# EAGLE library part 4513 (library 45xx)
BCD to 7-segment LATCH/DECODER/DRIVER

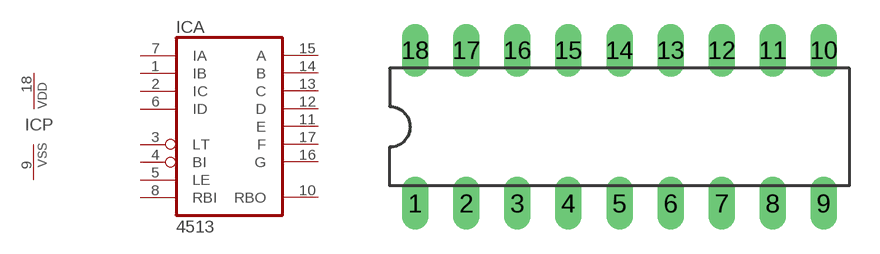
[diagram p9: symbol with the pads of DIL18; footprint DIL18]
Designator prefix IC; gates A=4513 P=PWRN

## 4513N  [DIL18]
1  A:IB  in
2  A:IC  in
3  A:LT  in
4  A:BI  in
5  A:LE  in
6  A:ID  in
7  A:IA  in
8  A:RBI  in
9  P:VSS  pwr
10  A:RBO  out
11  A:E  out
12  A:D  out
13  A:C  out
14  A:B  out
15  A:A  out
16  A:G  out
17  A:F  out
18  P:VDD  pwr

## Footprint DIL18 (pad centres in mm)
Dual In Line Package
drill 0.813 long: 1 -10.16,-3.81; 2 -7.62,-3.81; 3 -5.08,-3.81; 4 -2.54,-3.81; 5 0,-3.81; 6 2.54,-3.81; 7 5.08,-3.81; 8 7.62,-3.81; 9 10.16,-3.81; 10 10.16,3.81; 11 7.62,3.81; 12 5.08,3.81; 13 2.54,3.81; 14 0,3.81; 15 -2.54,3.81; 16 -5.08,3.81; 17 -7.62,3.81; 18 -10.16,3.81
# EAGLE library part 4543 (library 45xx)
BCD to 7-segment LCD DECODER

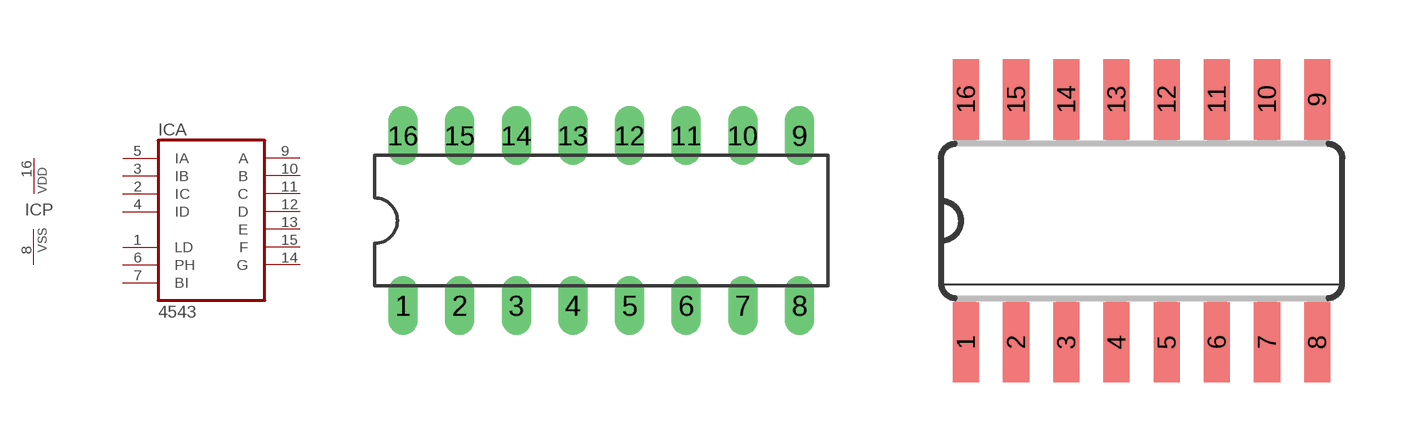
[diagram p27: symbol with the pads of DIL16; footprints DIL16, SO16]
Designator prefix IC; gates A=4543 P=PWRN

## 4543N  [DIL16]
1  A:LD  in
2  A:IC  in
3  A:IB  in
4  A:ID  in
5  A:IA  in
6  A:PH  in
7  A:BI  in
8  P:VSS  pwr
9  A:A  out
10  A:B  out
11  A:C  out
12  A:D  out
13  A:E  out
14  A:G  out
15  A:F  out
16  P:VDD  pwr

## 4543D  [SO16]
Pads as for DIL16

## Footprint DIL16 (pad centres in mm)
Dual In Line Package
drill 0.813 long: 1 -8.89,-3.81; 2 -6.35,-3.81; 3 -3.81,-3.81; 4 -1.27,-3.81; 5 1.27,-3.81; 6 3.81,-3.81; 7 6.35,-3.81; 8 8.89,-3.81; 9 8.89,3.81; 10 6.35,3.81; 11 3.81,3.81; 12 1.27,3.81; 13 -1.27,3.81; 14 -3.81,3.81; 15 -6.35,3.81; 16 -8.89,3.81

## Footprint SO16 (pad centres in mm)
Small Outline package 150 mil
smd 0.66 x 2.032: 1 -4.445,-3.073; 2 -3.175,-3.073; 3 -1.905,-3.073; 4 -0.635,-3.073; 5 0.635,-3.073; 6 1.905,-3.073; 7 3.175,-3.073; 8 4.445,-3.073; 9 4.445,3.073; 10 3.175,3.073; 11 1.905,3.073; 12 0.635,3.073; 13 -0.635,3.073; 14 -1.905,3.073; 15 -3.175,3.073; 16 -4.445,3.073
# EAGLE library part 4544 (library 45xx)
7-segment DECODER

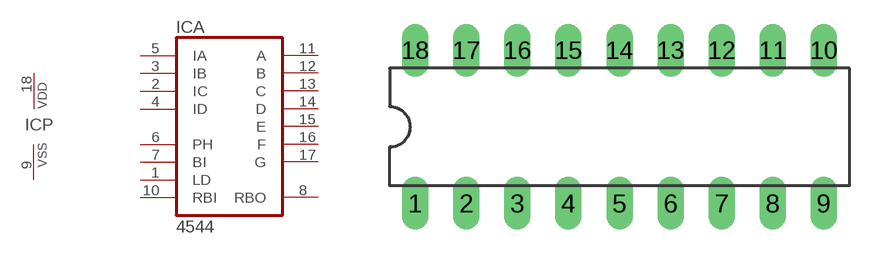
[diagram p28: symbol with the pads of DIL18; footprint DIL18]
Designator prefix IC; gates A=4544 P=PWRN

## 4544N  [DIL18]
1  A:LD  in
2  A:IC  in
3  A:IB  in
4  A:ID  in
5  A:IA  in
6  A:PH  in
7  A:BI  in
8  A:RBO  out
9  P:VSS  pwr
10  A:RBI  in
11  A:A  out
12  A:B  out
13  A:C  out
14  A:D  out
15  A:E  out
16  A:F  out
17  A:G  out
18  P:VDD  pwr

## Footprint DIL18 (pad centres in mm)
Dual In Line Package
drill 0.813 long: 1 -10.16,-3.81; 2 -7.62,-3.81; 3 -5.08,-3.81; 4 -2.54,-3.81; 5 0,-3.81; 6 2.54,-3.81; 7 5.08,-3.81; 8 7.62,-3.81; 9 10.16,-3.81; 10 10.16,3.81; 11 7.62,3.81; 12 5.08,3.81; 13 2.54,3.81; 14 0,3.81; 15 -2.54,3.81; 16 -5.08,3.81; 17 -7.62,3.81; 18 -10.16,3.81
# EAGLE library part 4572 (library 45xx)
INVERTER/OR/NOR (MC14572BCP)

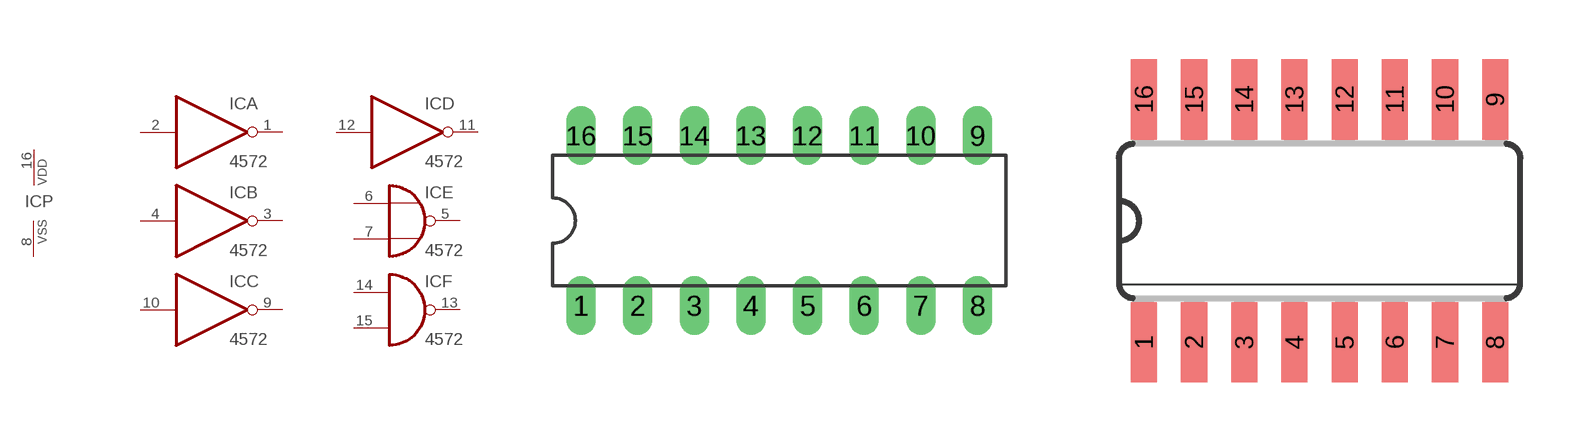
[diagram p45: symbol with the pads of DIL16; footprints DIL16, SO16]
Designator prefix IC; gates P=PWRN A=4572 B=4572 C=4572 D=4572 E=4572/A F=4572/B

## 4572N  [DIL16]
1  A:O  out
2  A:I  in
3  B:O  out
4  B:I  in
5  E:O  out
6  E:I0  in
7  E:I1  in
8  P:VSS  pwr
9  C:O  out
10  C:I  in
11  D:O  out
12  D:I  in
13  F:O  out
14  F:I0  in
15  F:I1  in
16  P:VDD  pwr

## 4572D  [SO16]
Pads as for DIL16

## Footprint DIL16 (pad centres in mm)
Dual In Line Package
drill 0.813 long: 1 -8.89,-3.81; 2 -6.35,-3.81; 3 -3.81,-3.81; 4 -1.27,-3.81; 5 1.27,-3.81; 6 3.81,-3.81; 7 6.35,-3.81; 8 8.89,-3.81; 9 8.89,3.81; 10 6.35,3.81; 11 3.81,3.81; 12 1.27,3.81; 13 -1.27,3.81; 14 -3.81,3.81; 15 -6.35,3.81; 16 -8.89,3.81

## Footprint SO16 (pad centres in mm)
Small Outline package 150 mil
smd 0.66 x 2.032: 1 -4.445,-3.073; 2 -3.175,-3.073; 3 -1.905,-3.073; 4 -0.635,-3.073; 5 0.635,-3.073; 6 1.905,-3.073; 7 3.175,-3.073; 8 4.445,-3.073; 9 4.445,3.073; 10 3.175,3.073; 11 1.905,3.073; 12 0.635,3.073; 13 -0.635,3.073; 14 -1.905,3.073; 15 -3.175,3.073; 16 -4.445,3.073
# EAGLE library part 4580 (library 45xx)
4 x 4 MULTIPORT REGISTER

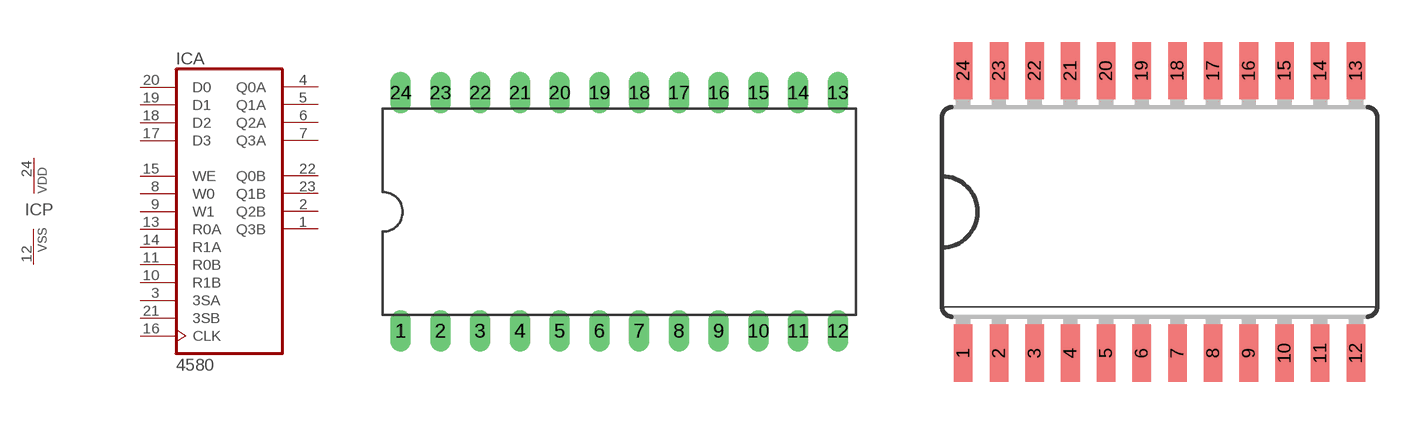
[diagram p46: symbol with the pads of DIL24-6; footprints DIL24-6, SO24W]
Designator prefix IC; gates A=4580 P=PWRN

## 4580N  [DIL24-6]
1  A:Q3B  out
2  A:Q2B  out
3  A:3SA  in
4  A:Q0A  out
5  A:Q1A  out
6  A:Q2A  out
7  A:Q3A  out
8  A:W0  in
9  A:W1  in
10  A:R1B  in
11  A:R0B  in
12  P:VSS  pwr
13  A:R0A  in
14  A:R1A  in
15  A:WE  in
16  A:CLK  in
17  A:D3  in
18  A:D2  in
19  A:D1  in
20  A:D0  in
21  A:3SB  in
22  A:Q0B  out
23  A:Q1B  out
24  P:VDD  pwr

## 4580D  [SO24W]
Pads as for DIL24-6

## Footprint DIL24-6 (pad centres in mm)
Dual In Line Package 0.6 inch
drill 0.813 long: 1 -13.97,-7.62; 2 -11.43,-7.62; 3 -8.89,-7.62; 4 -6.35,-7.62; 5 -3.81,-7.62; 6 -1.27,-7.62; 7 1.27,-7.62; 8 3.81,-7.62; 9 6.35,-7.62; 10 8.89,-7.62; 11 11.43,-7.62; 12 13.97,-7.62; 13 13.97,7.62; 14 11.43,7.62; 15 8.89,7.62; 16 6.35,7.62; 17 3.81,7.62; 18 1.27,7.62; 19 -1.27,7.62; 20 -3.81,7.62; 21 -6.35,7.62; 22 -8.89,7.62; 23 -11.43,7.62; 24 -13.97,7.62

## Footprint SO24W (pad centres in mm)
Wide Small Outline package 300 mil
smd 0.66 x 2.032: 1 -6.985,-5.029; 2 -5.715,-5.029; 3 -4.445,-5.029; 4 -3.175,-5.029; 5 -1.905,-5.029; 6 -0.635,-5.029; 7 0.635,-5.029; 8 1.905,-5.029; 9 3.175,-5.029; 10 4.445,-5.029; 11 5.715,-5.029; 12 6.985,-5.029; 13 6.985,5.029; 14 5.715,5.029; 15 4.445,5.029; 16 3.175,5.029; 17 1.905,5.029; 18 0.635,5.029; 19 -0.635,5.029; 20 -1.905,5.029; 21 -3.175,5.029; 22 -4.445,5.029; 23 -5.715,5.029; 24 -6.985,5.029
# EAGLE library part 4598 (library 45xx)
8-bit bus compatible LATCH

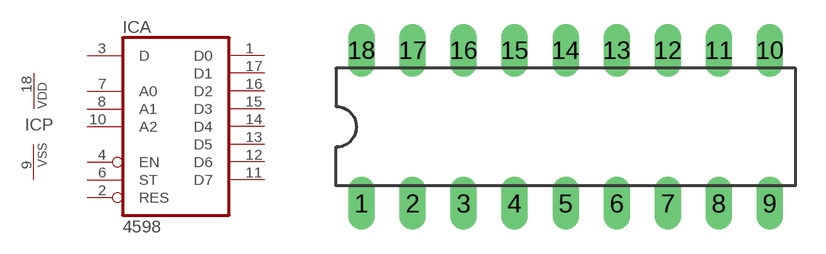
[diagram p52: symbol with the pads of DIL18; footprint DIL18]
Designator prefix IC; gates A=4598 P=PWRN

## 4598N  [DIL18]
1  A:D0  out
2  A:RES  in
3  A:D  in
4  A:EN  in
6  A:ST  in
7  A:A0  in
8  A:A1  in
9  P:VSS  pwr
10  A:A2  in
11  A:D7  out
12  A:D6  out
13  A:D5  out
14  A:D4  out
15  A:D3  out
16  A:D2  out
17  A:D1  out
18  P:VDD  pwr

## Footprint DIL18 (pad centres in mm)
Dual In Line Package
drill 0.813 long: 1 -10.16,-3.81; 2 -7.62,-3.81; 3 -5.08,-3.81; 4 -2.54,-3.81; 5 0,-3.81; 6 2.54,-3.81; 7 5.08,-3.81; 8 7.62,-3.81; 9 10.16,-3.81; 10 10.16,3.81; 11 7.62,3.81; 12 5.08,3.81; 13 2.54,3.81; 14 0,3.81; 15 -2.54,3.81; 16 -5.08,3.81; 17 -7.62,3.81; 18 -10.16,3.81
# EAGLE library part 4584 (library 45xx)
Hex SCHMITT TRIGGER (74C14)

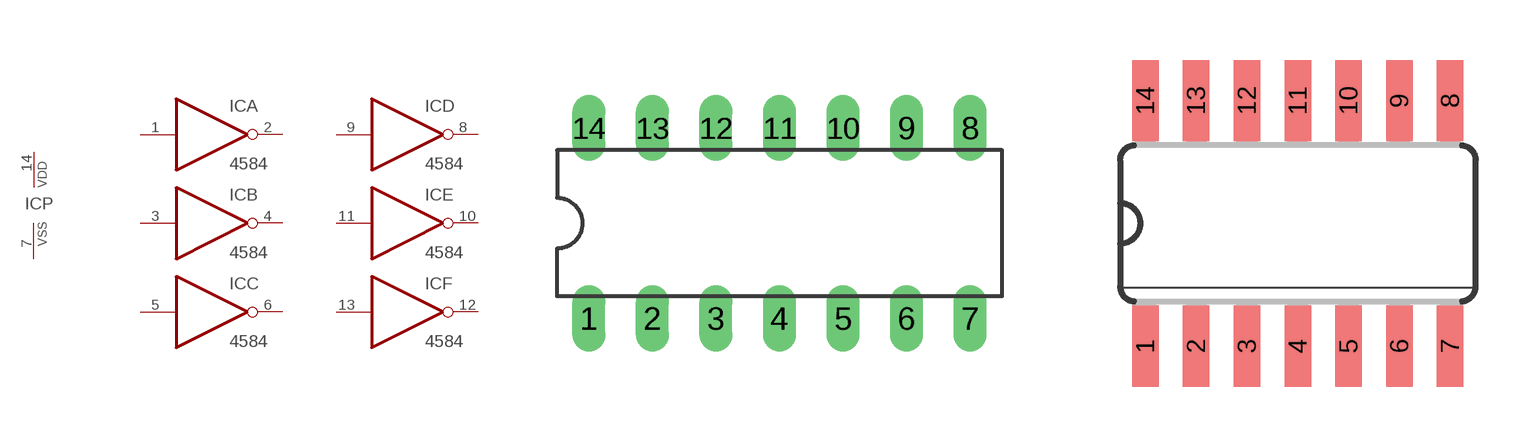
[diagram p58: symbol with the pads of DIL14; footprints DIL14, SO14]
Designator prefix IC; gates A=4584 B=4584 C=4584 D=4584 E=4584 F=4584 P=PWRN

## 4584N  [DIL14]
1  A:I  in
2  A:O  out
3  B:I  in
4  B:O  out
5  C:I  in
6  C:O  out
7  P:VSS  pwr
8  D:O  out
9  D:I  in
10  E:O  out
11  E:I  in
12  F:O  out
13  F:I  in
14  P:VDD  pwr

## 4584D  [SO14]
Pads as for DIL14

## Footprint DIL14 (pad centres in mm)
Dual In Line Package
drill 0.813 long: 1 -7.62,-3.81; 2 -5.08,-3.81; 3 -2.54,-3.81; 4 0,-3.81; 5 2.54,-3.81; 6 5.08,-3.81; 7 7.62,-3.81; 8 7.62,3.81; 9 5.08,3.81; 10 2.54,3.81; 11 0,3.81; 12 -2.54,3.81; 13 -5.08,3.81; 14 -7.62,3.81

## Footprint SO14 (pad centres in mm)
Small Outline package 150 mil
smd 0.66 x 2.032: 1 -3.81,-3.073; 2 -2.54,-3.073; 3 -1.27,-3.073; 4 0,-3.073; 5 1.27,-3.073; 6 2.54,-3.073; 7 3.81,-3.073; 8 3.81,3.073; 9 2.54,3.073; 10 1.27,3.073; 11 0,3.073; 12 -1.27,3.073; 13 -2.54,3.073; 14 -3.81,3.073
